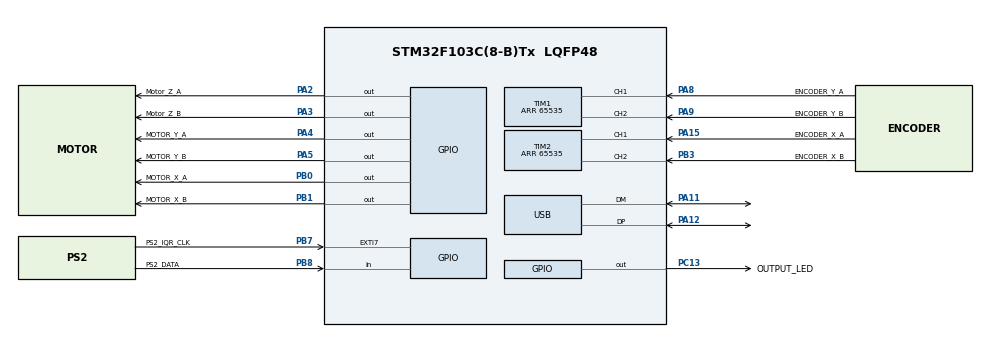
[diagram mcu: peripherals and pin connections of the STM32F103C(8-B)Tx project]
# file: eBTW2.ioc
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Mcu.Family=STM32F1
Mcu.Name=STM32F103C(8-B)Tx
Mcu.Package=LQFP48
NVIC.PriorityGroup=NVIC_PRIORITYGROUP_4
NVIC.USB_LP_CAN1_RX0_IRQn=true\:0\:0\:false\:false\:true\:false\:true
PA11.Mode=Device
PA11.Signal=USB_DM
PA12.Mode=Device
PA12.Signal=USB_DP
PA13.Mode=Serial_Wire
PA13.Signal=SYS_JTMS-SWDIO
PA14.Mode=Serial_Wire
PA14.Signal=SYS_JTCK-SWCLK
PA15.GPIO_Label=ENCODER_X_A
PA15.Signal=S_TIM2_CH1_ETR
PA2.GPIO_Label=Motor_Z_A
PA2.Signal=GPIO_Output
PA3.GPIO_Label=Motor_Z_B
PA3.Signal=GPIO_Output
PA4.GPIO_Label=MOTOR_Y_A
PA4.Signal=GPIO_Output
PA5.GPIO_Label=MOTOR_Y_B
PA5.Signal=GPIO_Output
PA8.GPIO_Label=ENCODER_Y_A
PA8.Signal=S_TIM1_CH1
PA9.GPIO_Label=ENCODER_Y_B
PA9.Signal=S_TIM1_CH2
PB0.GPIO_Label=MOTOR_X_A
PB0.Signal=GPIO_Output
PB1.GPIO_Label=MOTOR_X_B
PB1.Signal=GPIO_Output
PB3.GPIO_Label=ENCODER_X_B
PB3.Signal=S_TIM2_CH2
<<<<<<< HEAD:firmware/eBTW2.ioc
=======
PB7.GPIO_Label=PS2_IQR_CLK
PB7.Signal=GPXTI7
PB8.GPIO_Label=PS2_DATA
PB8.Signal=GPIO_Input
>>>>>>> parent of c309a30... Teclado funcionando:eBTW2.ioc
PC13-TAMPER-RTC.GPIO_Label=OUTPUT_LED
PC13-TAMPER-RTC.Signal=GPIO_Output
PD0-OSC_IN.Mode=HSE-External-Oscillator
PD0-OSC_IN.Signal=RCC_OSC_IN
PD1-OSC_OUT.Mode=HSE-External-Oscillator
PD1-OSC_OUT.Signal=RCC_OSC_OUT
ProjectManager.HeapSize=0x200
ProjectManager.StackSize=0x400
ProjectManager.TargetToolchain=STM32CubeIDE
RCC.AHBFreq_Value=48000000
RCC.APB1CLKDivider=RCC_HCLK_DIV2
RCC.APB1Freq_Value=24000000
RCC.APB1TimFreq_Value=48000000
RCC.APB2Freq_Value=48000000
RCC.APB2TimFreq_Value=48000000
RCC.HCLKFreq_Value=48000000
RCC.PLLMUL=RCC_PLL_MUL6
RCC.SYSCLKFreq_VALUE=48000000
RCC.SYSCLKSource=RCC_SYSCLKSOURCE_PLLCLK
RCC.USBFreq_Value=48000000
SH.S_TIM1_CH1.0=TIM1_CH1,Encoder_Interface
SH.S_TIM1_CH2.0=TIM1_CH2,Encoder_Interface
SH.S_TIM2_CH1_ETR.0=TIM2_CH1,Encoder_Interface
SH.S_TIM2_CH2.0=TIM2_CH2,Encoder_Interface
TIM1.Period=65535
TIM2.Period=65535
USB_DEVICE.CLASS_NAME_FS=CDC
USB_DEVICE.VirtualMode=Cdc
USB_DEVICE.VirtualModeFS=Cdc_FS
VP_USB_DEVICE_VS_USB_DEVICE_CDC_FS.Mode=CDC_FS
board=custom

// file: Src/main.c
/* USER CODE BEGIN Header */
/**
  ******************************************************************************
  * @file           : main.c
  * @brief          : Main program body
  ******************************************************************************
  * @attention
  *
  * <h2><center>&copy; Copyright (c) 2019 STMicroelectronics.
  * All rights reserved.</center></h2>
  *
  * This software component is licensed by ST under BSD 3-Clause license,
  * the "License"; You may not use this file except in compliance with the
  * License. You may obtain a copy of the License at:
  *                        opensource.org/licenses/BSD-3-Clause
  *
  ******************************************************************************
  */
/* USER CODE END Header */

#include "main.h"
#include "tim.h"
#include "gpio.h"

/* USER CODE BEGIN Includes */
#include "PS2Keyboard.h"
#include "brailleMatrix.h"
#include "DCMotors.h"
#include "stm32f1xx_it.h"
/* USER CODE END Includes */

/* USER CODE BEGIN PV */
#define MAX_CARACTERES 30
#define MAX_LINHAS 27
#define POS_INI 28000
#define POS_FIM 4000

char pressedEnter = 1;
char isEnd = 0;

Keyboard_TypeDef keyboard;

MotorControl_t motorX;
MotorControl_t motorY;

MotorControl_Simple_t motorZ;

unsigned char buffer_char[MAX_CARACTERES];
unsigned char buffer_braille[4];
/* USER CODE END PV */

void SystemClock_Config(void);

/* USER CODE BEGIN 0 */
void HAL_GPIO_EXTI_Callback(uint16_t GPIO_Pin){

	if(GPIO_Pin == keyboard.IQRPin){
		ps2interrupt(&keyboard);
	}

}
/* USER CODE END 0 */

int main(void)
{

  /* MCU Configuration--------------------------------------------------------*/

  /* Reset of all peripherals, Initializes the Flash interface and the Systick. */
  HAL_Init();

  /* Configure the system clock */
  SystemClock_Config();

  /* Initialize all configured peripherals */
  MX_GPIO_Init();
  MX_TIM2_Init();
  MX_TIM1_Init();
  /* USER CODE BEGIN 2 */
  HAL_TIM_Encoder_Start(&htim1, TIM_CHANNEL_ALL);
  HAL_TIM_Encoder_Start(&htim2, TIM_CHANNEL_ALL);

  motorBegin(&motorX, &htim2, MOTOR_X_A_GPIO_Port, MOTOR_X_A_Pin, MOTOR_X_B_GPIO_Port, MOTOR_X_B_Pin);
  motorBegin(&motorY, &htim1, MOTOR_Y_A_GPIO_Port, MOTOR_Y_A_Pin, MOTOR_Y_B_GPIO_Port, MOTOR_Y_B_Pin);

  //motorSimpleBegin(&motorZ, Motor_Z_A_GPIO_Port, Motor_Z_A_Pin, Motor_Z_B_GPIO_Port, Motor_Z_B_Pin);

  keyboardBegin(&keyboard, PS2_DATA_GPIO_Port, PS2_DATA_Pin, PS2_IQR_CLK_GPIO_Port, PS2_IQR_CLK_Pin);
  /* USER CODE END 2 */

  /* Infinite loop */
  while (1)
  {

    /* USER CODE BEGIN 3 */
	  //Faz a leitura do teclado e envia ao buffer_char
	  		while(1){
	  			if(keyboardAvailable(&keyboard)){
	  				HAL_GPIO_WritePin(OUTPUT_LED_GPIO_Port, OUTPUT_LED_Pin, GPIO_PIN_SET);
	  				HAL_Delay(100);
	  				HAL_GPIO_WritePin(OUTPUT_LED_GPIO_Port, OUTPUT_LED_Pin, GPIO_PIN_RESET);
	  				uint8_t c = keyboardRead(&keyboard);
	  				if(c == PS2_ENTER){
	  					pressedEnter = 1;
	  					HAL_GPIO_WritePin(OUTPUT_LED_GPIO_Port, OUTPUT_LED_Pin, GPIO_PIN_SET);
	  					break;
	  				}else if(c == PS2_DOWNARROW){
	  					updateAxis(&motorX, motorX.setPoint - 50);
	  				}else if(c == PS2_UPARROW){
	  					updateAxis(&motorX, motorX.setPoint + 50);
	  				}else if(c == PS2_LEFTARROW){
	  					updateAxis(&motorY, motorY.setPoint + 50);
	  				}else if(c == PS2_RIGHTARROW){
	  					updateAxis(&motorY, motorY.setPoint - 50);
	  				}else if(c == PS2_BACKSPACE){
	  					clearBuffer(buffer_char);
	  				}else{

	  					feedBuffer(buffer_char, MAX_CARACTERES, c);
	  				}
	  				keyboardClear(&keyboard);
	  			}
	  		}
	  		//Programa leitura do teclado
	  		if(pressedEnter){
	  			//reverse(buffer_char);
	  			uint32_t length = strlen((const char*)buffer_char);

	  			for(int j=0;j<3;j++){

	  				//Imprime as linhas em braille
	  				if(j==1){
	  					//Linhas das matrizes
	  					for(int8_t i=length-1; i>=0; --i){

	  						// Recebe os pontos da linha para o caractere atual
	  						fillLineWithBraille(buffer_braille, j,buffer_char[i]);

	  						// Percorre os 4 bits, no máximo, para cada caractere
	  						for(int8_t x = 0; x < 2; ++x){

	  							// Passa para a próxima iteração se não tem ponto para furar
	  							if(buffer_braille[x] == '1'){
	  								pierce(&motorZ, PIERCE_TIME);
	  							}

	  							if(x != 1){
	  								updateAxis(&motorX, motorX.setPoint - DELTA_COL_LIN);
	  							}

	  							// Incrementa posição do eixo x, espaçamento entre colunas

	  						}

	  						// Incrementa posição do eixo x, espaçamento entre char na horizontal
	  						if(i != 0){
	  							updateAxis(&motorX, motorX.setPoint - DELTA_CHAR_H);
	  						}

	  					}

	  					// Decrementa posição do eixo y, espaçamento entre linhas
	  					updateAxis(&motorY, motorY.setPoint - DELTA_COL_LIN);
	  					//updateAxis_Simple(&motorY, NEXT_LINE, UP);
	  				}else{

	  					//Linhas das matrizes
	  					for(int8_t i=0; i<length; i++){

	  						//Recebe os pontos da linha para o caractere atual
	  						fillLineWithBraille(buffer_braille, j,buffer_char[i]);

	  						//Percorre os 4 bits, no máximo, para cada caractere
	  						for(int8_t x = 1; x >= 0; --x){

	  							if(buffer_braille[x] == '1'){
	  								pierce(&motorZ, PIERCE_TIME);
	  							}

	  							// Incrementa posição do eixo x, espaçamento entre colunas
	  							if(x != 0){
	  								updateAxis(&motorX, motorX.setPoint + DELTA_COL_LIN);
	  							}

	  						}

	  						// Incrementa posição do eixo x, espaçamento entre char na horizontal
	  						if(i != (length -1)){
	  							updateAxis(&motorX, motorX.setPoint + DELTA_CHAR_H);
	  						}

	  					}

	  					// Incrementa posição do eixo y, espaçamento entre linhas
	  					updateAxis(&motorY, motorY.setPoint + DELTA_COL_LIN);
	  					//updateAxis_Simple(&motorY, NEXT_LINE, UP);
	  				}
	  			}

	  			//Incrementa posição do eixo y, espaçamento entre char na vertical
	  			updateAxis(&motorY, motorY.setPoint + DELTA_CHAR_V - DELTA_COL_LIN);
	  			//updateAxis_Simple(&motorY, NEXT_CHAR, UP);
	  			// Seta posição eixo x para inicial
	  			updateAxis(&motorX, POS_INI);

	  			pressedEnter = 0;
	  		}
	  		HAL_GPIO_WritePin(OUTPUT_LED_GPIO_Port, OUTPUT_LED_Pin, GPIO_PIN_RESET);
	  		keyboardClear(&keyboard);
	  		clearBuffer(buffer_char);

  }
  /* USER CODE END 3 */
}

void SystemClock_Config(void)
{
  RCC_OscInitTypeDef RCC_OscInitStruct = {0};
  RCC_ClkInitTypeDef RCC_ClkInitStruct = {0};

  /** Initializes the CPU, AHB and APB busses clocks
  */
  RCC_OscInitStruct.OscillatorType = RCC_OSCILLATORTYPE_HSI;
  RCC_OscInitStruct.HSIState = RCC_HSI_ON;
  RCC_OscInitStruct.HSICalibrationValue = RCC_HSICALIBRATION_DEFAULT;
  RCC_OscInitStruct.PLL.PLLState = RCC_PLL_NONE;
  if (HAL_RCC_OscConfig(&RCC_OscInitStruct) != HAL_OK)
  {
    Error_Handler();
  }
  /** Initializes the CPU, AHB and APB busses clocks
  */
  RCC_ClkInitStruct.ClockType = RCC_CLOCKTYPE_HCLK|RCC_CLOCKTYPE_SYSCLK
                              |RCC_CLOCKTYPE_PCLK1|RCC_CLOCKTYPE_PCLK2;
  RCC_ClkInitStruct.SYSCLKSource = RCC_SYSCLKSOURCE_HSI;
  RCC_ClkInitStruct.AHBCLKDivider = RCC_SYSCLK_DIV1;
  RCC_ClkInitStruct.APB1CLKDivider = RCC_HCLK_DIV1;
  RCC_ClkInitStruct.APB2CLKDivider = RCC_HCLK_DIV1;

  if (HAL_RCC_ClockConfig(&RCC_ClkInitStruct, FLASH_LATENCY_0) != HAL_OK)
  {
    Error_Handler();
  }
}

void Error_Handler(void)
{
}

/************************ (C) COPYRIGHT STMicroelectronics *****END OF FILE****/
